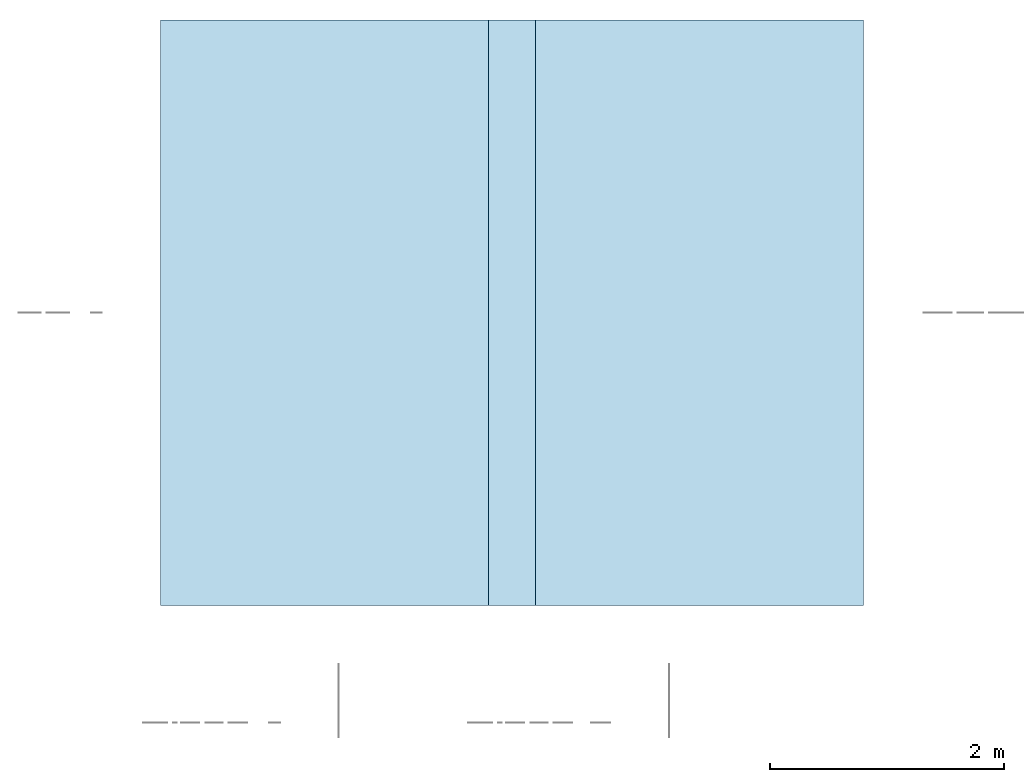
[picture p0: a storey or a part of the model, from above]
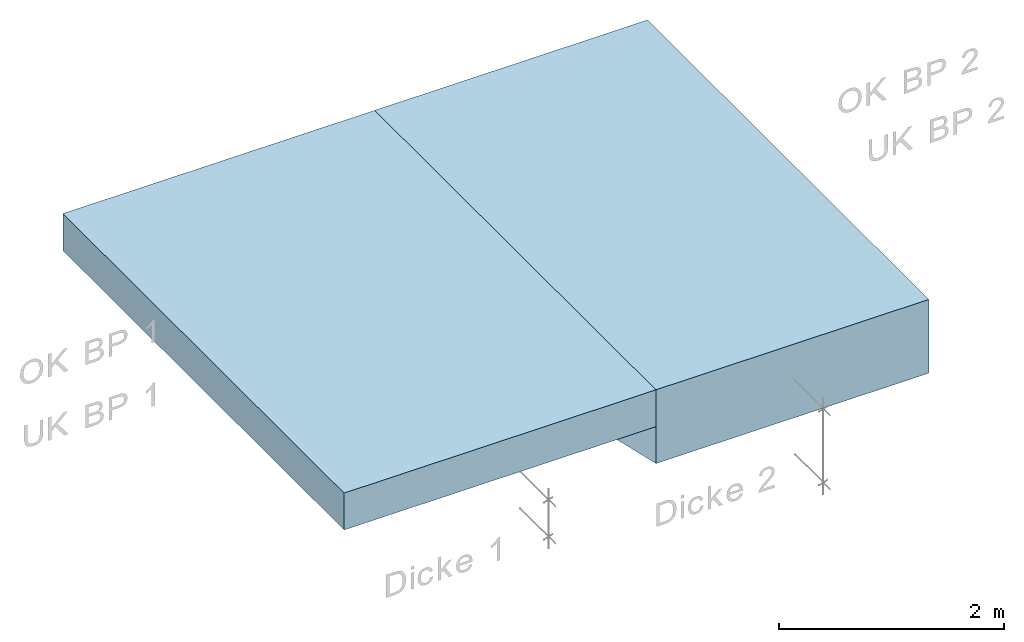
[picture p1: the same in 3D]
Properties of the parts of a building model (IFC4)

# File
Description: no view
File name: ÖBV_OEBV_Richtlinie_Bodenplatte.ifc
Time: 2024-03-13T09:34:11
Author: Oesterreichische Bautechnik Vereinigung
Organization: OEBV
Written by: ODA SDAI 24.5
Authorization: OEBV

# IfcSite, Liegenschaft
RefLatitude: 48, 8, 10, 320000; RefLongitude: 11, 41, 19, 320000

# IfcBuildingStorey, Geschoss 01
In: Gebäude
Elevation: 0 m

# IfcBuildingElementProxy (8)
In: Geschoss 01
Name | Allright_Bauteil_ID
 | 0004Mak0000000158
macro | 0004Mak0000000059
macro | 0004Mak0000000085
macro | 0004Mak0000000048
macro | 0004Mak0000000072
macro | 0004Mak0000007517
macro | 0004Mak0000007529
macro | 0004Mak0000010699

# IfcElementAssembly (8)
In: Geschoss 01
Name | Allright_Bauteil_ID
SpatialDim_Group | 0004Elg0000000027
SpatialDim_Group | 0004Elg0000000060
SpatialDim_Group | 0004Elg0000000086
SpatialDim_Group | 0004Elg0000000049
SpatialDim_Group | 0004Elg0000000073
SpatialDim_Group | 0004Elg0000000123
SpatialDim_Group | 0004Elg0000000038
SpatialDim_Group | 0004Elg0000000135

# IfcSlab (3)
In: Geschoss 01
Description: Plattenfundament; PredefinedType: BASESLAB; Material: C20/25
Name | Allright_Bauteil_ID
 | 0004ErE0000009623
 | 0004De 0000013909
 | 0004De 0000013913
